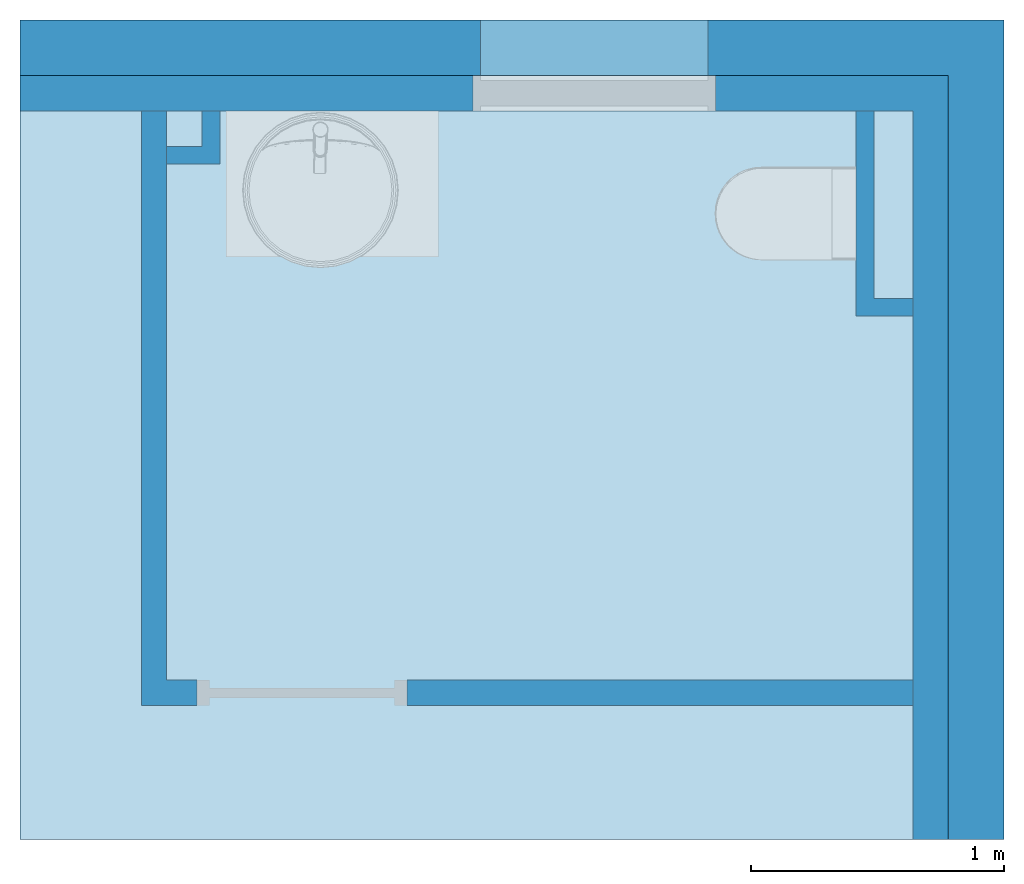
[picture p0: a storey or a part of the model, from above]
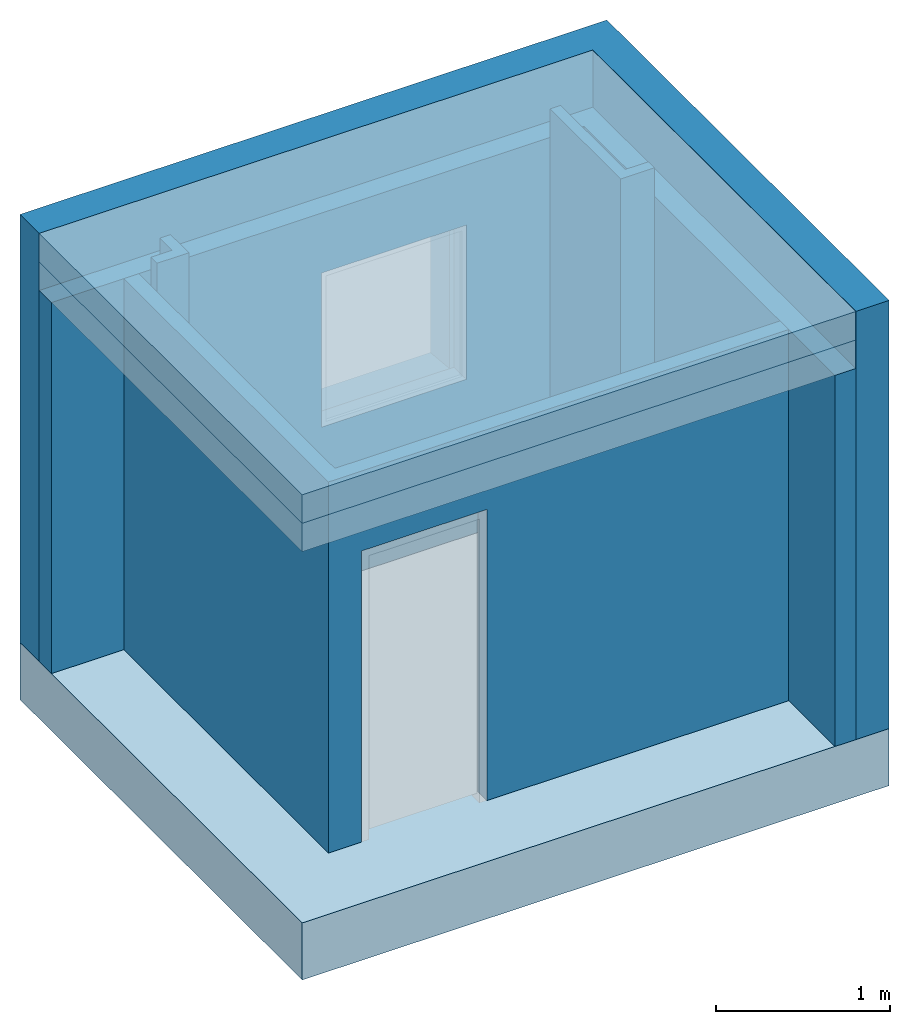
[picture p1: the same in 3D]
Properties of the parts of a building model (IFC4)

# File
Description: ViewDefinition [TrimBim], ExchangeRequirement [Any]
File name: BIM SDB RDC.ifc
Time: 2023-01-18T13:23:10
Author: olivier.perrin
Organization: Trimble
Written by: Trimble SketchUp
Made in: Trimble SketchUp
Authorization: IFC4 model

# IfcSpace
salle de bain - ObjectType: SketchupComponentInstance

# IfcBuildingElementProxy (4)
Name | Group, ObjectType
 | vb_kerami1 - ObjectType: SketchupComponentInstance
3 x  | SketchupGroup

# IfcDoor, Int. Simple:PP (0.83m x 2.04m):273715
Int. Simple:PP (0.83m x 2.04m):273715 - Description: Int. Simple:PP (0.83m x 2.04m):273715; ObjectType: SketchupComponentInstance

# IfcSlab (3)
Name
 | Plafond composé:Plafond avec isolation - ObjectType: SketchupComponentInstance
 | PLANCHER BAS SOL FINI - ObjectType: SketchupComponentInstance
 | PLANCHER HAUT - ObjectType: SketchupComponentInstance

# IfcWall (5)
Name
 | Mur de base:Générique - Int. 140mm - ObjectType: SketchupComponentInstance
 | Mur de base:Générique - Int. 100mm - ObjectType: SketchupComponentInstance
 | Mur de base:Générique - Int. 70 mm:261084 - ObjectType: SketchupComponentInstance
 | Mur de base:Générique - Int. 70 mm - ObjectType: SketchupComponentInstance
 | MURS PORTEURS 220 MM - ObjectType: SketchupComponentInstance

# IfcWindow
Chassis Fixe-0.90m x 1.05m - ObjectType: SketchupComponentInstance
